VERSION 5.8 ;
BUSBITCHARS "[]" ;
DIVIDERCHAR "/" ;
UNITS
    DATABASE MICRONS 1000 ;
END UNITS

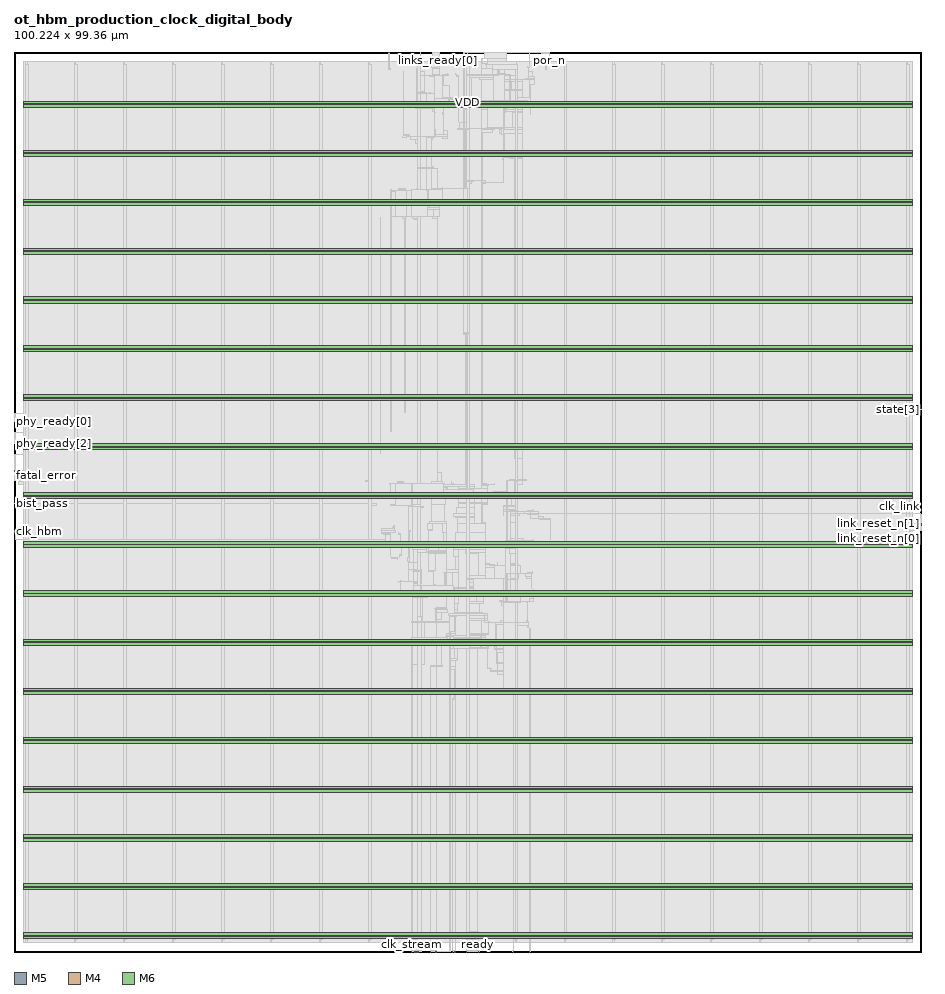
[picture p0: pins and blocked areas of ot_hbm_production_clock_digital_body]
MACRO ot_hbm_production_clock_digital_body
  FOREIGN ot_hbm_production_clock_digital_body 0 0 ;
  CLASS BLOCK ;
  SIZE 100.224 BY 99.36 ;
  PIN aon_clk
    DIRECTION INPUT ;
    USE SIGNAL ;
    PORT
      LAYER M5 ;
        RECT  58.368 99.276 58.392 99.36 ;
    END
  END aon_clk
  PIN bist_done
    DIRECTION INPUT ;
    USE SIGNAL ;
    PORT
      LAYER M5 ;
        RECT  54.336 99.276 54.36 99.36 ;
    END
  END bist_done
  PIN bist_pass
    DIRECTION INPUT ;
    USE SIGNAL ;
    PORT
      LAYER M4 ;
        RECT  0 49.536 0.084 49.56 ;
    END
  END bist_pass
  PIN clk_hbm
    DIRECTION INPUT ;
    USE SIGNAL ;
    PORT
      LAYER M4 ;
        RECT  0 46.464 0.084 46.488 ;
    END
  END clk_hbm
  PIN clk_link
    DIRECTION INPUT ;
    USE SIGNAL ;
    PORT
      LAYER M4 ;
        RECT  100.14 48.288 100.224 48.312 ;
    END
  END clk_link
  PIN clk_serial
    DIRECTION INPUT ;
    USE SIGNAL ;
    PORT
      LAYER M5 ;
        RECT  46.56 0 46.584 0.084 ;
    END
  END clk_serial
  PIN clk_stream
    DIRECTION INPUT ;
    USE SIGNAL ;
    PORT
      LAYER M5 ;
        RECT  43.872 0 43.896 0.084 ;
    END
  END clk_stream
  PIN cmd_reset_serial_n
    DIRECTION OUTPUT ;
    USE SIGNAL ;
    PORT
      LAYER M5 ;
        RECT  56.928 0 56.952 0.084 ;
    END
  END cmd_reset_serial_n
  PIN cmd_reset_stream_n
    DIRECTION OUTPUT ;
    USE SIGNAL ;
    PORT
      LAYER M5 ;
        RECT  55.104 0 55.128 0.084 ;
    END
  END cmd_reset_stream_n
  PIN coll_reset_serial_n
    DIRECTION OUTPUT ;
    USE SIGNAL ;
    PORT
      LAYER M5 ;
        RECT  48.384 0 48.408 0.084 ;
    END
  END coll_reset_serial_n
  PIN coll_reset_stream_n
    DIRECTION OUTPUT ;
    USE SIGNAL ;
    PORT
      LAYER M5 ;
        RECT  45.984 0 46.008 0.084 ;
    END
  END coll_reset_stream_n
  PIN fatal_error
    DIRECTION INPUT ;
    USE SIGNAL ;
    PORT
      LAYER M4 ;
        RECT  0 52.608 0.084 52.632 ;
    END
  END fatal_error
  PIN link_reset_n[0]
    DIRECTION OUTPUT ;
    USE SIGNAL ;
    PORT
      LAYER M4 ;
        RECT  100.14 46.56 100.224 46.584 ;
    END
  END link_reset_n[0]
  PIN link_reset_n[1]
    DIRECTION OUTPUT ;
    USE SIGNAL ;
    PORT
      LAYER M4 ;
        RECT  100.14 47.328 100.224 47.352 ;
    END
  END link_reset_n[1]
  PIN link_reset_n[2]
    DIRECTION OUTPUT ;
    USE SIGNAL ;
    PORT
      LAYER M4 ;
        RECT  100.14 46.848 100.224 46.872 ;
    END
  END link_reset_n[2]
  PIN link_reset_n[3]
    DIRECTION OUTPUT ;
    USE SIGNAL ;
    PORT
      LAYER M4 ;
        RECT  100.14 46.944 100.224 46.968 ;
    END
  END link_reset_n[3]
  PIN link_reset_n[4]
    DIRECTION OUTPUT ;
    USE SIGNAL ;
    PORT
      LAYER M4 ;
        RECT  100.14 47.232 100.224 47.256 ;
    END
  END link_reset_n[4]
  PIN link_reset_n[5]
    DIRECTION OUTPUT ;
    USE SIGNAL ;
    PORT
      LAYER M4 ;
        RECT  100.14 46.752 100.224 46.776 ;
    END
  END link_reset_n[5]
  PIN link_reset_n[6]
    DIRECTION OUTPUT ;
    USE SIGNAL ;
    PORT
      LAYER M4 ;
        RECT  100.14 47.04 100.224 47.064 ;
    END
  END link_reset_n[6]
  PIN link_reset_n[7]
    DIRECTION OUTPUT ;
    USE SIGNAL ;
    PORT
      LAYER M4 ;
        RECT  100.14 47.136 100.224 47.16 ;
    END
  END link_reset_n[7]
  PIN link_reset_n[8]
    DIRECTION OUTPUT ;
    USE SIGNAL ;
    PORT
      LAYER M4 ;
        RECT  100.14 46.656 100.224 46.68 ;
    END
  END link_reset_n[8]
  PIN links_ready[0]
    DIRECTION INPUT ;
    USE SIGNAL ;
    PORT
      LAYER M5 ;
        RECT  46.752 99.276 46.776 99.36 ;
    END
  END links_ready[0]
  PIN links_ready[1]
    DIRECTION INPUT ;
    USE SIGNAL ;
    PORT
      LAYER M5 ;
        RECT  46.944 99.276 46.968 99.36 ;
    END
  END links_ready[1]
  PIN links_ready[2]
    DIRECTION INPUT ;
    USE SIGNAL ;
    PORT
      LAYER M5 ;
        RECT  53.472 99.276 53.496 99.36 ;
    END
  END links_ready[2]
  PIN links_ready[3]
    DIRECTION INPUT ;
    USE SIGNAL ;
    PORT
      LAYER M5 ;
        RECT  52.224 99.276 52.248 99.36 ;
    END
  END links_ready[3]
  PIN links_ready[4]
    DIRECTION INPUT ;
    USE SIGNAL ;
    PORT
      LAYER M5 ;
        RECT  56.928 99.276 56.952 99.36 ;
    END
  END links_ready[4]
  PIN links_ready[5]
    DIRECTION INPUT ;
    USE SIGNAL ;
    PORT
      LAYER M5 ;
        RECT  52.8 99.276 52.824 99.36 ;
    END
  END links_ready[5]
  PIN links_ready[6]
    DIRECTION INPUT ;
    USE SIGNAL ;
    PORT
      LAYER M5 ;
        RECT  50.016 99.276 50.04 99.36 ;
    END
  END links_ready[6]
  PIN links_ready[7]
    DIRECTION INPUT ;
    USE SIGNAL ;
    PORT
      LAYER M5 ;
        RECT  44.832 99.276 44.856 99.36 ;
    END
  END links_ready[7]
  PIN links_ready[8]
    DIRECTION INPUT ;
    USE SIGNAL ;
    PORT
      LAYER M5 ;
        RECT  46.176 99.276 46.2 99.36 ;
    END
  END links_ready[8]
  PIN phy_ready[0]
    DIRECTION INPUT ;
    USE SIGNAL ;
    PORT
      LAYER M4 ;
        RECT  0 58.56 0.084 58.584 ;
    END
  END phy_ready[0]
  PIN phy_ready[1]
    DIRECTION INPUT ;
    USE SIGNAL ;
    PORT
      LAYER M5 ;
        RECT  41.376 99.276 41.4 99.36 ;
    END
  END phy_ready[1]
  PIN phy_ready[2]
    DIRECTION INPUT ;
    USE SIGNAL ;
    PORT
      LAYER M4 ;
        RECT  0 56.16 0.084 56.184 ;
    END
  END phy_ready[2]
  PIN phy_ready[3]
    DIRECTION INPUT ;
    USE SIGNAL ;
    PORT
      LAYER M4 ;
        RECT  0 54.048 0.084 54.072 ;
    END
  END phy_ready[3]
  PIN phy_reset_n[0]
    DIRECTION OUTPUT ;
    USE SIGNAL ;
    PORT
      LAYER M5 ;
        RECT  44.544 0 44.568 0.084 ;
    END
  END phy_reset_n[0]
  PIN phy_reset_n[1]
    DIRECTION OUTPUT ;
    USE SIGNAL ;
    PORT
      LAYER M5 ;
        RECT  44.256 0 44.28 0.084 ;
    END
  END phy_reset_n[1]
  PIN phy_reset_n[2]
    DIRECTION OUTPUT ;
    USE SIGNAL ;
    PORT
      LAYER M5 ;
        RECT  44.352 0 44.376 0.084 ;
    END
  END phy_reset_n[2]
  PIN phy_reset_n[3]
    DIRECTION OUTPUT ;
    USE SIGNAL ;
    PORT
      LAYER M5 ;
        RECT  44.448 0 44.472 0.084 ;
    END
  END phy_reset_n[3]
  PIN pll_lock
    DIRECTION INPUT ;
    USE SIGNAL ;
    PORT
      LAYER M5 ;
        RECT  44.64 0 44.664 0.084 ;
    END
  END pll_lock
  PIN pll_reset_n
    DIRECTION OUTPUT ;
    USE SIGNAL ;
    PORT
      LAYER M5 ;
        RECT  49.92 0 49.944 0.084 ;
    END
  END pll_reset_n
  PIN por_n
    DIRECTION INPUT ;
    USE SIGNAL ;
    PORT
      LAYER M5 ;
        RECT  59.136 99.276 59.16 99.36 ;
    END
  END por_n
  PIN power_good
    DIRECTION INPUT ;
    USE SIGNAL ;
    PORT
      LAYER M4 ;
        RECT  0 52.032 0.084 52.056 ;
    END
  END power_good
  PIN ready
    DIRECTION OUTPUT ;
    USE SIGNAL ;
    PORT
      LAYER M5 ;
        RECT  51.264 0 51.288 0.084 ;
    END
  END ready
  PIN requalify
    DIRECTION INPUT ;
    USE SIGNAL ;
    PORT
      LAYER M4 ;
        RECT  0 53.088 0.084 53.112 ;
    END
  END requalify
  PIN state[0]
    DIRECTION OUTPUT ;
    USE SIGNAL ;
    PORT
      LAYER M5 ;
        RECT  46.656 0 46.68 0.084 ;
    END
  END state[0]
  PIN state[1]
    DIRECTION OUTPUT ;
    USE SIGNAL ;
    PORT
      LAYER M5 ;
        RECT  48.672 0 48.696 0.084 ;
    END
  END state[1]
  PIN state[2]
    DIRECTION OUTPUT ;
    USE SIGNAL ;
    PORT
      LAYER M5 ;
        RECT  51.936 99.276 51.96 99.36 ;
    END
  END state[2]
  PIN state[3]
    DIRECTION OUTPUT ;
    USE SIGNAL ;
    PORT
      LAYER M4 ;
        RECT  100.14 59.904 100.224 59.928 ;
    END
  END state[3]
  PIN VDD
    DIRECTION INOUT ;
    USE POWER ;
    PORT
      LAYER M6 ;
        RECT  1.08 93.633 99.144 93.921 ;
        RECT  1.08 88.233 99.144 88.521 ;
        RECT  1.08 82.833 99.144 83.121 ;
        RECT  1.08 77.433 99.144 77.721 ;
        RECT  1.08 72.033 99.144 72.321 ;
        RECT  1.08 66.633 99.144 66.921 ;
        RECT  1.08 61.233 99.144 61.521 ;
        RECT  1.08 55.833 99.144 56.121 ;
        RECT  1.08 50.433 99.144 50.721 ;
        RECT  1.08 45.033 99.144 45.321 ;
        RECT  1.08 39.633 99.144 39.921 ;
        RECT  1.08 34.233 99.144 34.521 ;
        RECT  1.08 28.833 99.144 29.121 ;
        RECT  1.08 23.433 99.144 23.721 ;
        RECT  1.08 18.033 99.144 18.321 ;
        RECT  1.08 12.633 99.144 12.921 ;
        RECT  1.08 7.233 99.144 7.521 ;
        RECT  1.08 1.833 99.144 2.121 ;
    END
  END VDD
  PIN VSS
    DIRECTION INOUT ;
    USE GROUND ;
    PORT
      LAYER M6 ;
        RECT  1.08 93.249 99.144 93.537 ;
        RECT  1.08 87.849 99.144 88.137 ;
        RECT  1.08 82.449 99.144 82.737 ;
        RECT  1.08 77.049 99.144 77.337 ;
        RECT  1.08 71.649 99.144 71.937 ;
        RECT  1.08 66.249 99.144 66.537 ;
        RECT  1.08 60.849 99.144 61.137 ;
        RECT  1.08 55.449 99.144 55.737 ;
        RECT  1.08 50.049 99.144 50.337 ;
        RECT  1.08 44.649 99.144 44.937 ;
        RECT  1.08 39.249 99.144 39.537 ;
        RECT  1.08 33.849 99.144 34.137 ;
        RECT  1.08 28.449 99.144 28.737 ;
        RECT  1.08 23.049 99.144 23.337 ;
        RECT  1.08 17.649 99.144 17.937 ;
        RECT  1.08 12.249 99.144 12.537 ;
        RECT  1.08 6.849 99.144 7.137 ;
        RECT  1.08 1.449 99.144 1.737 ;
    END
  END VSS
  OBS
    LAYER RVTN ;
     RECT  1.08 1.08 99.144 1.215 ;
     RECT  1.08 1.485 99.144 1.755 ;
     RECT  1.08 2.025 99.144 2.295 ;
     RECT  1.08 2.565 99.144 2.835 ;
     RECT  1.08 3.105 99.144 3.375 ;
     RECT  1.08 3.645 99.144 3.915 ;
     RECT  1.08 4.185 99.144 4.455 ;
     RECT  1.08 4.725 99.144 4.995 ;
     RECT  1.08 5.265 99.144 5.535 ;
     RECT  1.08 5.805 99.144 6.075 ;
     RECT  1.08 6.345 99.144 6.615 ;
     RECT  1.08 6.885 99.144 7.155 ;
     RECT  1.08 7.425 99.144 7.695 ;
     RECT  1.08 7.965 99.144 8.235 ;
     RECT  1.08 8.505 99.144 8.775 ;
     RECT  1.08 9.045 99.144 9.315 ;
     RECT  1.08 9.585 99.144 9.855 ;
     RECT  1.08 10.125 99.144 10.395 ;
     RECT  1.08 10.665 99.144 10.935 ;
     RECT  1.08 11.205 99.144 11.475 ;
     RECT  1.08 11.745 99.144 12.015 ;
     RECT  1.08 12.285 99.144 12.555 ;
     RECT  1.08 12.825 99.144 13.095 ;
     RECT  1.08 13.365 99.144 13.635 ;
     RECT  1.08 13.905 99.144 14.175 ;
     RECT  1.08 14.445 99.144 14.715 ;
     RECT  1.08 14.985 99.144 15.255 ;
     RECT  1.08 15.525 99.144 15.795 ;
     RECT  1.08 16.065 99.144 16.335 ;
     RECT  1.08 16.605 99.144 16.875 ;
     RECT  1.08 17.145 99.144 17.415 ;
     RECT  1.08 17.685 99.144 17.955 ;
     RECT  1.08 18.225 99.144 18.495 ;
     RECT  1.08 18.765 99.144 19.035 ;
     RECT  1.08 19.305 99.144 19.575 ;
     RECT  1.08 19.845 99.144 20.115 ;
     RECT  1.08 20.385 99.144 20.655 ;
     RECT  1.08 20.925 99.144 21.195 ;
     RECT  1.08 21.465 99.144 21.735 ;
     RECT  1.08 22.005 99.144 22.275 ;
     RECT  1.08 22.545 99.144 22.815 ;
     RECT  1.08 23.085 99.144 23.355 ;
     RECT  1.08 23.625 99.144 23.895 ;
     RECT  1.08 24.165 99.144 24.435 ;
     RECT  1.08 24.705 99.144 24.975 ;
     RECT  1.08 25.245 99.144 25.515 ;
     RECT  1.08 25.785 99.144 26.055 ;
     RECT  1.08 26.325 99.144 26.595 ;
     RECT  1.08 26.865 99.144 27.135 ;
     RECT  1.08 27.405 99.144 27.675 ;
     RECT  1.08 27.945 99.144 28.215 ;
     RECT  1.08 28.485 99.144 28.755 ;
     RECT  1.08 29.025 99.144 29.295 ;
     RECT  1.08 29.565 99.144 29.835 ;
     RECT  1.08 30.105 99.144 30.375 ;
     RECT  1.08 30.645 99.144 30.915 ;
     RECT  1.08 31.185 99.144 31.455 ;
     RECT  1.08 31.725 99.144 31.995 ;
     RECT  1.08 32.265 99.144 32.535 ;
     RECT  1.08 32.805 99.144 33.075 ;
     RECT  1.08 33.345 99.144 33.615 ;
     RECT  1.08 33.885 99.144 34.155 ;
     RECT  1.08 34.425 99.144 34.695 ;
     RECT  1.08 34.965 99.144 35.235 ;
     RECT  1.08 35.505 99.144 35.775 ;
     RECT  1.08 36.045 99.144 36.315 ;
     RECT  1.08 36.585 99.144 36.855 ;
     RECT  1.08 37.125 99.144 37.395 ;
     RECT  1.08 37.665 99.144 37.935 ;
     RECT  1.08 38.205 99.144 38.475 ;
     RECT  1.08 38.745 99.144 39.015 ;
     RECT  1.08 39.285 99.144 39.555 ;
     RECT  1.08 39.825 99.144 40.095 ;
     RECT  1.08 40.365 99.144 40.635 ;
     RECT  1.08 40.905 99.144 41.175 ;
     RECT  1.08 41.445 99.144 41.715 ;
     RECT  1.08 41.985 99.144 42.255 ;
     RECT  1.08 42.525 99.144 42.795 ;
     RECT  1.08 43.065 99.144 43.335 ;
     RECT  1.08 43.605 99.144 43.875 ;
     RECT  1.08 44.145 99.144 44.415 ;
     RECT  1.08 44.685 99.144 44.955 ;
     RECT  1.08 45.225 99.144 45.495 ;
     RECT  1.08 45.765 99.144 46.035 ;
     RECT  1.08 46.305 99.144 46.575 ;
     RECT  1.08 46.845 99.144 47.115 ;
     RECT  1.08 47.385 99.144 47.655 ;
     RECT  1.08 47.925 99.144 48.195 ;
     RECT  1.08 48.465 99.144 48.735 ;
     RECT  1.08 49.005 99.144 49.275 ;
     RECT  1.08 49.545 99.144 49.815 ;
     RECT  1.08 50.085 99.144 50.355 ;
     RECT  1.08 50.625 99.144 50.895 ;
     RECT  1.08 51.165 99.144 51.435 ;
     RECT  1.08 51.705 99.144 51.975 ;
     RECT  1.08 52.245 99.144 52.515 ;
     RECT  1.08 52.785 99.144 53.055 ;
     RECT  1.08 53.325 99.144 53.595 ;
     RECT  1.08 53.865 99.144 54.135 ;
     RECT  1.08 54.405 99.144 54.675 ;
     RECT  1.08 54.945 99.144 55.215 ;
     RECT  1.08 55.485 99.144 55.755 ;
     RECT  1.08 56.025 99.144 56.295 ;
     RECT  1.08 56.565 99.144 56.835 ;
     RECT  1.08 57.105 99.144 57.375 ;
     RECT  1.08 57.645 99.144 57.915 ;
     RECT  1.08 58.185 99.144 58.455 ;
     RECT  1.08 58.725 99.144 58.995 ;
     RECT  1.08 59.265 99.144 59.535 ;
     RECT  1.08 59.805 99.144 60.075 ;
     RECT  1.08 60.345 99.144 60.615 ;
     RECT  1.08 60.885 99.144 61.155 ;
     RECT  1.08 61.425 99.144 61.695 ;
     RECT  1.08 61.965 99.144 62.235 ;
     RECT  1.08 62.505 99.144 62.775 ;
     RECT  1.08 63.045 99.144 63.315 ;
     RECT  1.08 63.585 99.144 63.855 ;
     RECT  1.08 64.125 99.144 64.395 ;
     RECT  1.08 64.665 99.144 64.935 ;
     RECT  1.08 65.205 99.144 65.475 ;
     RECT  1.08 65.745 99.144 66.015 ;
     RECT  1.08 66.285 99.144 66.555 ;
     RECT  1.08 66.825 99.144 67.095 ;
     RECT  1.08 67.365 99.144 67.635 ;
     RECT  1.08 67.905 99.144 68.175 ;
     RECT  1.08 68.445 99.144 68.715 ;
     RECT  1.08 68.985 99.144 69.255 ;
     RECT  1.08 69.525 99.144 69.795 ;
     RECT  1.08 70.065 99.144 70.335 ;
     RECT  1.08 70.605 99.144 70.875 ;
     RECT  1.08 71.145 99.144 71.415 ;
     RECT  1.08 71.685 99.144 71.955 ;
     RECT  1.08 72.225 99.144 72.495 ;
     RECT  1.08 72.765 99.144 73.035 ;
     RECT  1.08 73.305 99.144 73.575 ;
     RECT  1.08 73.845 99.144 74.115 ;
     RECT  1.08 74.385 99.144 74.655 ;
     RECT  1.08 74.925 99.144 75.195 ;
     RECT  1.08 75.465 99.144 75.735 ;
     RECT  1.08 76.005 99.144 76.275 ;
     RECT  1.08 76.545 99.144 76.815 ;
     RECT  1.08 77.085 99.144 77.355 ;
     RECT  1.08 77.625 99.144 77.895 ;
     RECT  1.08 78.165 99.144 78.435 ;
     RECT  1.08 78.705 99.144 78.975 ;
     RECT  1.08 79.245 99.144 79.515 ;
     RECT  1.08 79.785 99.144 80.055 ;
     RECT  1.08 80.325 99.144 80.595 ;
     RECT  1.08 80.865 99.144 81.135 ;
     RECT  1.08 81.405 99.144 81.675 ;
     RECT  1.08 81.945 99.144 82.215 ;
     RECT  1.08 82.485 99.144 82.755 ;
     RECT  1.08 83.025 99.144 83.295 ;
     RECT  1.08 83.565 99.144 83.835 ;
     RECT  1.08 84.105 99.144 84.375 ;
     RECT  1.08 84.645 99.144 84.915 ;
     RECT  1.08 85.185 99.144 85.455 ;
     RECT  1.08 85.725 99.144 85.995 ;
     RECT  1.08 86.265 99.144 86.535 ;
     RECT  1.08 86.805 99.144 87.075 ;
     RECT  1.08 87.345 99.144 87.615 ;
     RECT  1.08 87.885 99.144 88.155 ;
     RECT  1.08 88.425 99.144 88.695 ;
     RECT  1.08 88.965 99.144 89.235 ;
     RECT  1.08 89.505 99.144 89.775 ;
     RECT  1.08 90.045 99.144 90.315 ;
     RECT  1.08 90.585 99.144 90.855 ;
     RECT  1.08 91.125 99.144 91.395 ;
     RECT  1.08 91.665 99.144 91.935 ;
     RECT  1.08 92.205 99.144 92.475 ;
     RECT  1.08 92.745 99.144 93.015 ;
     RECT  1.08 93.285 99.144 93.555 ;
     RECT  1.08 93.825 99.144 94.095 ;
     RECT  1.08 94.365 99.144 94.635 ;
     RECT  1.08 94.905 99.144 95.175 ;
     RECT  1.08 95.445 99.144 95.715 ;
     RECT  1.08 95.985 99.144 96.255 ;
     RECT  1.08 96.525 99.144 96.795 ;
     RECT  1.08 97.065 99.144 97.335 ;
     RECT  1.08 97.605 99.144 97.875 ;
     RECT  1.08 98.145 99.144 98.28 ;
    LAYER RVTP ;
     RECT  1.08 1.215 99.144 1.485 ;
     RECT  1.08 1.755 99.144 2.025 ;
     RECT  1.08 2.295 99.144 2.565 ;
     RECT  1.08 2.835 99.144 3.105 ;
     RECT  1.08 3.375 99.144 3.645 ;
     RECT  1.08 3.915 99.144 4.185 ;
     RECT  1.08 4.455 99.144 4.725 ;
     RECT  1.08 4.995 99.144 5.265 ;
     RECT  1.08 5.535 99.144 5.805 ;
     RECT  1.08 6.075 99.144 6.345 ;
     RECT  1.08 6.615 99.144 6.885 ;
     RECT  1.08 7.155 99.144 7.425 ;
     RECT  1.08 7.695 99.144 7.965 ;
     RECT  1.08 8.235 99.144 8.505 ;
     RECT  1.08 8.775 99.144 9.045 ;
     RECT  1.08 9.315 99.144 9.585 ;
     RECT  1.08 9.855 99.144 10.125 ;
     RECT  1.08 10.395 99.144 10.665 ;
     RECT  1.08 10.935 99.144 11.205 ;
     RECT  1.08 11.475 99.144 11.745 ;
     RECT  1.08 12.015 99.144 12.285 ;
     RECT  1.08 12.555 99.144 12.825 ;
     RECT  1.08 13.095 99.144 13.365 ;
     RECT  1.08 13.635 99.144 13.905 ;
     RECT  1.08 14.175 99.144 14.445 ;
     RECT  1.08 14.715 99.144 14.985 ;
     RECT  1.08 15.255 99.144 15.525 ;
     RECT  1.08 15.795 99.144 16.065 ;
     RECT  1.08 16.335 99.144 16.605 ;
     RECT  1.08 16.875 99.144 17.145 ;
     RECT  1.08 17.415 99.144 17.685 ;
     RECT  1.08 17.955 99.144 18.225 ;
     RECT  1.08 18.495 99.144 18.765 ;
     RECT  1.08 19.035 99.144 19.305 ;
     RECT  1.08 19.575 99.144 19.845 ;
     RECT  1.08 20.115 99.144 20.385 ;
     RECT  1.08 20.655 99.144 20.925 ;
     RECT  1.08 21.195 99.144 21.465 ;
     RECT  1.08 21.735 99.144 22.005 ;
     RECT  1.08 22.275 99.144 22.545 ;
     RECT  1.08 22.815 99.144 23.085 ;
     RECT  1.08 23.355 99.144 23.625 ;
     RECT  1.08 23.895 99.144 24.165 ;
     RECT  1.08 24.435 99.144 24.705 ;
     RECT  1.08 24.975 99.144 25.245 ;
     RECT  1.08 25.515 99.144 25.785 ;
     RECT  1.08 26.055 99.144 26.325 ;
     RECT  1.08 26.595 99.144 26.865 ;
     RECT  1.08 27.135 99.144 27.405 ;
     RECT  1.08 27.675 99.144 27.945 ;
     RECT  1.08 28.215 99.144 28.485 ;
     RECT  1.08 28.755 99.144 29.025 ;
     RECT  1.08 29.295 99.144 29.565 ;
     RECT  1.08 29.835 99.144 30.105 ;
     RECT  1.08 30.375 99.144 30.645 ;
     RECT  1.08 30.915 99.144 31.185 ;
     RECT  1.08 31.455 99.144 31.725 ;
     RECT  1.08 31.995 99.144 32.265 ;
     RECT  1.08 32.535 99.144 32.805 ;
     RECT  1.08 33.075 99.144 33.345 ;
     RECT  1.08 33.615 99.144 33.885 ;
     RECT  1.08 34.155 99.144 34.425 ;
     RECT  1.08 34.695 99.144 34.965 ;
     RECT  1.08 35.235 99.144 35.505 ;
     RECT  1.08 35.775 99.144 36.045 ;
     RECT  1.08 36.315 99.144 36.585 ;
     RECT  1.08 36.855 99.144 37.125 ;
     RECT  1.08 37.395 99.144 37.665 ;
     RECT  1.08 37.935 99.144 38.205 ;
     RECT  1.08 38.475 99.144 38.745 ;
     RECT  1.08 39.015 99.144 39.285 ;
     RECT  1.08 39.555 99.144 39.825 ;
     RECT  1.08 40.095 99.144 40.365 ;
     RECT  1.08 40.635 99.144 40.905 ;
     RECT  1.08 41.175 99.144 41.445 ;
     RECT  1.08 41.715 99.144 41.985 ;
     RECT  1.08 42.255 99.144 42.525 ;
     RECT  1.08 42.795 99.144 43.065 ;
     RECT  1.08 43.335 99.144 43.605 ;
     RECT  1.08 43.875 99.144 44.145 ;
     RECT  1.08 44.415 99.144 44.685 ;
     RECT  1.08 44.955 99.144 45.225 ;
     RECT  1.08 45.495 99.144 45.765 ;
     RECT  1.08 46.035 99.144 46.305 ;
     RECT  1.08 46.575 99.144 46.845 ;
     RECT  1.08 47.115 99.144 47.385 ;
     RECT  1.08 47.655 99.144 47.925 ;
     RECT  1.08 48.195 99.144 48.465 ;
     RECT  1.08 48.735 99.144 49.005 ;
     RECT  1.08 49.275 99.144 49.545 ;
     RECT  1.08 49.815 99.144 50.085 ;
     RECT  1.08 50.355 99.144 50.625 ;
     RECT  1.08 50.895 99.144 51.165 ;
     RECT  1.08 51.435 99.144 51.705 ;
     RECT  1.08 51.975 99.144 52.245 ;
     RECT  1.08 52.515 99.144 52.785 ;
     RECT  1.08 53.055 99.144 53.325 ;
     RECT  1.08 53.595 99.144 53.865 ;
     RECT  1.08 54.135 99.144 54.405 ;
     RECT  1.08 54.675 99.144 54.945 ;
     RECT  1.08 55.215 99.144 55.485 ;
     RECT  1.08 55.755 99.144 56.025 ;
     RECT  1.08 56.295 99.144 56.565 ;
     RECT  1.08 56.835 99.144 57.105 ;
     RECT  1.08 57.375 99.144 57.645 ;
     RECT  1.08 57.915 99.144 58.185 ;
     RECT  1.08 58.455 99.144 58.725 ;
     RECT  1.08 58.995 99.144 59.265 ;
     RECT  1.08 59.535 99.144 59.805 ;
     RECT  1.08 60.075 99.144 60.345 ;
     RECT  1.08 60.615 99.144 60.885 ;
     RECT  1.08 61.155 99.144 61.425 ;
     RECT  1.08 61.695 99.144 61.965 ;
     RECT  1.08 62.235 99.144 62.505 ;
     RECT  1.08 62.775 99.144 63.045 ;
     RECT  1.08 63.315 99.144 63.585 ;
     RECT  1.08 63.855 99.144 64.125 ;
     RECT  1.08 64.395 99.144 64.665 ;
     RECT  1.08 64.935 99.144 65.205 ;
     RECT  1.08 65.475 99.144 65.745 ;
     RECT  1.08 66.015 99.144 66.285 ;
     RECT  1.08 66.555 99.144 66.825 ;
     RECT  1.08 67.095 99.144 67.365 ;
     RECT  1.08 67.635 99.144 67.905 ;
     RECT  1.08 68.175 99.144 68.445 ;
     RECT  1.08 68.715 99.144 68.985 ;
     RECT  1.08 69.255 99.144 69.525 ;
     RECT  1.08 69.795 99.144 70.065 ;
     RECT  1.08 70.335 99.144 70.605 ;
     RECT  1.08 70.875 99.144 71.145 ;
     RECT  1.08 71.415 99.144 71.685 ;
     RECT  1.08 71.955 99.144 72.225 ;
     RECT  1.08 72.495 99.144 72.765 ;
     RECT  1.08 73.035 99.144 73.305 ;
     RECT  1.08 73.575 99.144 73.845 ;
     RECT  1.08 74.115 99.144 74.385 ;
     RECT  1.08 74.655 99.144 74.925 ;
     RECT  1.08 75.195 99.144 75.465 ;
     RECT  1.08 75.735 99.144 76.005 ;
     RECT  1.08 76.275 99.144 76.545 ;
     RECT  1.08 76.815 99.144 77.085 ;
     RECT  1.08 77.355 99.144 77.625 ;
     RECT  1.08 77.895 99.144 78.165 ;
     RECT  1.08 78.435 99.144 78.705 ;
     RECT  1.08 78.975 99.144 79.245 ;
     RECT  1.08 79.515 99.144 79.785 ;
     RECT  1.08 80.055 99.144 80.325 ;
     RECT  1.08 80.595 99.144 80.865 ;
     RECT  1.08 81.135 99.144 81.405 ;
     RECT  1.08 81.675 99.144 81.945 ;
     RECT  1.08 82.215 99.144 82.485 ;
     RECT  1.08 82.755 99.144 83.025 ;
     RECT  1.08 83.295 99.144 83.565 ;
     RECT  1.08 83.835 99.144 84.105 ;
     RECT  1.08 84.375 99.144 84.645 ;
     RECT  1.08 84.915 99.144 85.185 ;
     RECT  1.08 85.455 99.144 85.725 ;
     RECT  1.08 85.995 99.144 86.265 ;
     RECT  1.08 86.535 99.144 86.805 ;
     RECT  1.08 87.075 99.144 87.345 ;
     RECT  1.08 87.615 99.144 87.885 ;
     RECT  1.08 88.155 99.144 88.425 ;
     RECT  1.08 88.695 99.144 88.965 ;
     RECT  1.08 89.235 99.144 89.505 ;
     RECT  1.08 89.775 99.144 90.045 ;
     RECT  1.08 90.315 99.144 90.585 ;
     RECT  1.08 90.855 99.144 91.125 ;
     RECT  1.08 91.395 99.144 91.665 ;
     RECT  1.08 91.935 99.144 92.205 ;
     RECT  1.08 92.475 99.144 92.745 ;
     RECT  1.08 93.015 99.144 93.285 ;
     RECT  1.08 93.555 99.144 93.825 ;
     RECT  1.08 94.095 99.144 94.365 ;
     RECT  1.08 94.635 99.144 94.905 ;
     RECT  1.08 95.175 99.144 95.445 ;
     RECT  1.08 95.715 99.144 95.985 ;
     RECT  1.08 96.255 99.144 96.525 ;
     RECT  1.08 96.795 99.144 97.065 ;
     RECT  1.08 97.335 99.144 97.605 ;
     RECT  1.08 97.875 99.144 98.145 ;
    LAYER M1 ;
     RECT  1.08 1.071 99.144 98.289 ;
    LAYER M2 ;
     RECT  0.499 51.642 0.535 51.66 ;
     RECT  0.535 51.642 1.08 51.966 ;
     RECT  0.535 52.992 1.08 53.01 ;
     RECT  0.103 54.882 1.08 54.9 ;
     RECT  0.103 57.312 1.08 57.33 ;
     RECT  0.103 59.472 1.08 59.49 ;
     RECT  1.08 1.071 99.144 98.289 ;
     RECT  99.144 47.124 99.167 47.214 ;
     RECT  99.167 47.124 99.203 47.142 ;
    LAYER M3 ;
     RECT  46.008 0.091 46.026 0.523 ;
     RECT  44.136 0.091 44.154 0.811 ;
     RECT  44.136 0.811 44.478 0.907 ;
     RECT  44.136 0.907 44.514 1.063 ;
     RECT  55.116 0.091 55.134 1.063 ;
     RECT  1.335 1.063 1.425 1.333 ;
     RECT  6.735 1.063 6.825 1.333 ;
     RECT  12.135 1.063 12.225 1.333 ;
     RECT  17.535 1.063 17.625 1.333 ;
     RECT  22.935 1.063 23.025 1.333 ;
     RECT  28.335 1.063 28.425 1.333 ;
     RECT  33.735 1.063 33.825 1.333 ;
     RECT  39.135 1.063 39.225 1.333 ;
     RECT  44.136 1.063 44.625 1.333 ;
     RECT  49.935 1.063 50.025 1.333 ;
     RECT  50.904 0.091 51.282 1.333 ;
     RECT  55.116 1.063 55.425 1.333 ;
     RECT  60.735 1.063 60.825 1.333 ;
     RECT  66.135 1.063 66.225 1.333 ;
     RECT  71.535 1.063 71.625 1.333 ;
     RECT  76.935 1.063 77.025 1.333 ;
     RECT  82.335 1.063 82.425 1.333 ;
     RECT  87.735 1.063 87.825 1.333 ;
     RECT  93.135 1.063 93.225 1.333 ;
     RECT  98.535 1.063 98.625 1.333 ;
     RECT  44.136 1.333 44.817 1.795 ;
     RECT  49.935 1.333 51.282 2.219 ;
     RECT  48.708 0.091 48.726 27.931 ;
     RECT  48.528 27.931 48.726 28.139 ;
     RECT  55.116 1.333 55.617 28.409 ;
     RECT  54.072 28.417 54.09 30.685 ;
     RECT  52.632 30.955 52.65 30.991 ;
     RECT  53.388 30.685 54.09 30.991 ;
     RECT  52.632 30.991 54.09 31.109 ;
     RECT  48.6 28.139 48.726 31.225 ;
     RECT  52.632 31.109 52.65 31.325 ;
     RECT  46.008 0.523 46.674 31.495 ;
     RECT  48.024 31.225 48.726 31.523 ;
     RECT  46.008 31.495 47.178 31.531 ;
     RECT  46.008 31.531 47.358 31.649 ;
     RECT  43.992 1.795 44.817 31.765 ;
     RECT  53.424 31.109 54.09 31.891 ;
     RECT  53.316 31.891 54.09 31.919 ;
     RECT  48.132 31.523 48.726 32.161 ;
     RECT  48.132 32.161 48.942 32.369 ;
     RECT  53.316 31.919 53.334 33.115 ;
     RECT  54.072 31.919 54.09 33.115 ;
     RECT  53.316 33.115 54.09 33.385 ;
     RECT  49.935 2.219 51.21 33.511 ;
     RECT  52.992 33.385 54.09 33.539 ;
     RECT  52.236 33.547 52.254 33.611 ;
     RECT  52.992 33.539 53.226 33.683 ;
     RECT  48.672 32.369 48.942 33.925 ;
     RECT  49.86 33.511 51.21 33.925 ;
     RECT  52.092 33.691 52.11 33.925 ;
     RECT  48.672 33.925 52.11 34.079 ;
     RECT  46.656 31.649 47.178 34.231 ;
     RECT  46.656 34.231 47.538 34.393 ;
     RECT  48.672 34.079 52.002 34.393 ;
     RECT  46.656 34.393 52.002 34.397 ;
     RECT  47.628 34.397 52.002 34.727 ;
     RECT  47.7 34.727 52.002 34.889 ;
     RECT  47.7 34.889 48.906 34.925 ;
     RECT  49.935 34.889 52.002 35.041 ;
     RECT  47.7 34.925 48.726 35.159 ;
     RECT  49.935 35.041 52.398 35.159 ;
     RECT  48.096 35.159 48.726 35.357 ;
     RECT  56.952 0.091 56.97 35.699 ;
     RECT  53.208 33.683 53.226 36.085 ;
     RECT  55.335 28.409 55.617 36.085 ;
     RECT  56.664 35.815 56.754 36.085 ;
     RECT  53.208 36.085 53.298 36.121 ;
     RECT  54.072 33.539 54.09 36.121 ;
     RECT  55.335 36.085 56.754 36.331 ;
     RECT  53.136 36.121 54.09 36.347 ;
     RECT  43.992 31.765 45.27 36.379 ;
     RECT  53.28 36.347 54.09 36.383 ;
     RECT  55.332 36.331 56.754 36.383 ;
     RECT  52.38 35.159 52.398 36.391 ;
     RECT  43.848 36.379 45.27 36.419 ;
     RECT  52.38 36.391 52.542 36.509 ;
     RECT  56.628 36.383 56.754 36.509 ;
     RECT  53.748 36.383 54.09 36.545 ;
     RECT  56.628 36.509 56.682 36.545 ;
     RECT  49.935 35.159 51.57 36.625 ;
     RECT  46.656 34.397 46.674 36.661 ;
     RECT  49.935 36.625 52.326 36.779 ;
     RECT  48.636 35.357 48.726 37.051 ;
     RECT  48.096 37.051 48.726 37.057 ;
     RECT  48.096 37.057 48.906 37.201 ;
     RECT  49.935 36.779 52.29 37.201 ;
     RECT  47.952 37.201 52.29 37.319 ;
     RECT  48.636 37.319 51.75 37.427 ;
     RECT  46.656 36.661 47.214 37.435 ;
     RECT  49.935 37.427 51.75 37.463 ;
     RECT  48.636 37.427 49.014 37.769 ;
     RECT  46.656 37.435 47.826 37.859 ;
     RECT  46.656 37.859 47.718 37.867 ;
     RECT  46.512 37.867 47.718 37.931 ;
     RECT  46.656 37.931 47.718 38.003 ;
     RECT  46.656 38.003 46.674 38.129 ;
     RECT  54.072 36.545 54.09 38.209 ;
     RECT  48.672 37.769 49.014 38.479 ;
     RECT  48.672 38.479 49.05 38.515 ;
     RECT  49.935 37.463 51.39 38.515 ;
     RECT  53.82 38.209 54.09 38.551 ;
     RECT  55.335 36.383 55.617 38.551 ;
     RECT  56.664 36.545 56.682 38.551 ;
     RECT  49.935 38.515 51.858 38.669 ;
     RECT  53.82 38.551 55.617 38.669 ;
     RECT  54.396 38.669 55.617 38.677 ;
     RECT  56.592 38.551 56.682 38.677 ;
     RECT  54.396 38.677 57.33 38.717 ;
     RECT  56.592 38.717 57.33 38.741 ;
     RECT  53.64 38.713 53.658 38.765 ;
     RECT  54.396 38.717 55.617 38.975 ;
     RECT  56.88 38.741 57.33 38.975 ;
     RECT  43.992 36.419 45.09 39.091 ;
     RECT  43.992 39.091 45.63 39.209 ;
     RECT  45.612 39.209 45.63 39.245 ;
     RECT  54.72 38.975 55.617 39.479 ;
     RECT  57.312 38.975 57.33 40.055 ;
     RECT  48.672 38.515 49.086 40.135 ;
     RECT  49.935 38.669 51.066 40.135 ;
     RECT  45.936 39.253 46.35 40.171 ;
     RECT  48.672 40.135 51.066 40.171 ;
     RECT  48.492 40.171 51.066 40.261 ;
     RECT  45.936 40.171 46.962 40.289 ;
     RECT  48.456 40.261 51.066 40.289 ;
     RECT  49.935 40.289 51.066 40.333 ;
     RECT  51.84 38.669 51.858 40.333 ;
     RECT  45.936 40.289 46.53 40.369 ;
     RECT  45.756 40.369 46.53 40.445 ;
     RECT  46.332 40.445 46.53 40.595 ;
     RECT  43.992 39.209 44.874 40.639 ;
     RECT  42.624 40.639 42.642 40.711 ;
     RECT  43.596 40.639 44.874 40.711 ;
     RECT  42.624 40.711 45.018 40.829 ;
     RECT  49.935 40.333 51.858 40.837 ;
     RECT  43.308 40.829 45.018 40.865 ;
     RECT  43.416 40.865 45.018 40.901 ;
     RECT  42.48 40.837 42.498 40.925 ;
     RECT  54.828 39.479 55.617 41.131 ;
     RECT  54.396 41.131 55.617 41.171 ;
     RECT  54.792 41.171 55.617 41.251 ;
     RECT  57.096 40.171 57.114 41.251 ;
     RECT  56.556 41.251 57.114 41.413 ;
     RECT  49.935 40.837 52.038 41.549 ;
     RECT  54.792 41.251 55.71 41.755 ;
     RECT  56.52 41.413 57.114 41.755 ;
     RECT  47.7 38.003 47.718 41.791 ;
     RECT  54.792 41.755 57.114 41.791 ;
     RECT  54.792 41.791 57.258 41.792 ;
     RECT  47.664 41.791 47.718 41.851 ;
     RECT  47.52 41.851 47.718 41.909 ;
     RECT  56.7 41.792 57.258 41.909 ;
     RECT  47.7 41.909 47.718 41.917 ;
     RECT  48.456 40.289 49.086 41.917 ;
     RECT  57.24 41.909 57.258 41.981 ;
     RECT  46.332 40.595 46.35 42.061 ;
     RECT  45.792 42.061 46.35 42.151 ;
     RECT  43.596 40.901 45.018 42.179 ;
     RECT  43.596 42.179 44.874 42.215 ;
     RECT  47.7 41.917 49.086 42.215 ;
     RECT  52.02 41.549 52.038 42.421 ;
     RECT  53.064 41.341 53.082 42.421 ;
     RECT  54.792 41.792 55.89 42.719 ;
     RECT  54.792 42.719 55.71 42.791 ;
     RECT  52.02 42.421 53.082 42.827 ;
     RECT  52.02 42.827 52.542 42.863 ;
     RECT  54.792 42.791 55.638 42.863 ;
     RECT  43.596 42.215 44.817 42.989 ;
     RECT  53.352 42.835 53.37 42.989 ;
     RECT  43.596 42.989 43.614 43.141 ;
     RECT  42.3 43.303 42.318 43.411 ;
     RECT  43.488 43.141 43.614 43.529 ;
     RECT  41.724 43.411 42.318 43.565 ;
     RECT  48.708 42.215 49.086 43.645 ;
     RECT  42.516 43.573 42.534 43.771 ;
     RECT  42.516 43.771 42.786 43.871 ;
     RECT  45.792 42.151 46.53 43.951 ;
     RECT  49.935 41.549 51.282 43.951 ;
     RECT  45.792 43.951 46.854 44.041 ;
     RECT  47.7 42.215 47.718 44.041 ;
     RECT  54.792 42.863 55.617 44.041 ;
     RECT  49.86 43.951 51.282 44.077 ;
     RECT  52.02 42.863 52.038 44.077 ;
     RECT  45.792 44.041 47.718 44.149 ;
     RECT  45.54 44.149 47.718 44.189 ;
     RECT  45.792 44.189 47.718 44.375 ;
     RECT  48.528 43.645 49.086 44.383 ;
     RECT  49.86 44.077 52.038 44.383 ;
     RECT  54.684 44.041 55.617 44.587 ;
     RECT  54.252 44.587 55.617 44.645 ;
     RECT  41.58 43.609 41.598 44.725 ;
     RECT  46.836 44.375 47.718 44.879 ;
     RECT  48.528 44.383 52.038 44.879 ;
     RECT  54.396 44.645 55.617 44.879 ;
     RECT  54.72 44.879 55.617 44.959 ;
     RECT  41.58 44.725 41.922 44.971 ;
     RECT  54.72 44.959 55.926 44.987 ;
     RECT  41.328 44.971 41.922 45.005 ;
     RECT  54.792 44.987 55.926 45.031 ;
     RECT  42.768 43.871 42.786 45.149 ;
     RECT  54.792 45.031 56.61 45.157 ;
     RECT  41.328 45.005 41.598 45.193 ;
     RECT  54.792 45.157 56.898 45.301 ;
     RECT  54.792 45.301 57.33 45.455 ;
     RECT  57.312 45.455 57.33 45.527 ;
     RECT  54.792 45.455 56.214 45.599 ;
     RECT  41.004 45.193 41.598 46.111 ;
     RECT  42.66 45.265 42.678 46.111 ;
     RECT  98.535 1.333 98.817 46.111 ;
     RECT  45.792 44.375 45.81 46.201 ;
     RECT  42.408 46.111 42.678 46.229 ;
     RECT  40.752 46.111 41.598 46.237 ;
     RECT  42.408 46.229 42.426 46.265 ;
     RECT  40.608 46.237 41.598 46.273 ;
     RECT  48.78 44.879 52.038 46.301 ;
     RECT  43.596 43.529 43.614 46.345 ;
     RECT  47.376 44.879 47.718 46.345 ;
     RECT  98.535 46.111 98.946 46.345 ;
     RECT  43.524 46.345 43.614 46.381 ;
     RECT  40.608 46.273 42.066 46.499 ;
     RECT  43.524 46.381 43.758 46.499 ;
     RECT  45.756 46.201 45.81 46.579 ;
     RECT  45.756 46.579 46.206 46.615 ;
     RECT  40.608 46.499 41.958 46.769 ;
     RECT  41.436 46.769 41.958 46.805 ;
     RECT  41.796 46.805 41.958 46.841 ;
     RECT  98.496 46.345 98.946 46.921 ;
     RECT  98.496 46.921 99.018 46.939 ;
     RECT  41.868 46.841 41.958 47.039 ;
     RECT  98.496 46.939 99.162 47.047 ;
     RECT  41.868 47.039 41.886 47.075 ;
     RECT  98.244 47.047 99.162 47.119 ;
     RECT  98.244 47.119 99.198 47.261 ;
     RECT  59.256 45.571 59.274 47.309 ;
     RECT  98.244 47.261 99.018 47.309 ;
     RECT  45.648 46.615 46.206 47.345 ;
     RECT  48.96 46.301 52.038 47.345 ;
     RECT  45.864 47.345 46.206 47.353 ;
     RECT  47.268 46.345 47.718 47.353 ;
     RECT  98.535 47.309 99.018 47.357 ;
     RECT  51.588 47.345 52.038 47.381 ;
     RECT  54.792 45.599 55.617 47.417 ;
     RECT  45.864 47.353 47.718 47.579 ;
     RECT  59.184 47.461 59.202 47.731 ;
     RECT  58.068 47.731 59.202 47.834 ;
     RECT  57.924 47.834 59.202 47.849 ;
     RECT  57.924 47.849 58.77 47.885 ;
     RECT  48.96 47.345 50.814 48.001 ;
     RECT  48.744 48.001 50.814 48.091 ;
     RECT  57.924 47.885 58.482 48.119 ;
     RECT  54.828 47.417 55.617 48.235 ;
     RECT  56.988 47.851 57.006 48.271 ;
     RECT  57.924 48.119 57.942 48.271 ;
     RECT  54.828 48.235 55.818 48.379 ;
     RECT  48.528 48.091 50.814 48.389 ;
     RECT  54.828 48.379 55.926 48.425 ;
     RECT  54.072 48.235 54.09 48.619 ;
     RECT  54.828 48.425 55.617 48.619 ;
     RECT  56.736 48.271 57.942 48.659 ;
     RECT  56.736 48.659 57.33 48.695 ;
     RECT  56.988 48.695 57.33 48.701 ;
     RECT  54.072 48.619 55.617 48.811 ;
     RECT  57.312 48.701 57.33 48.839 ;
     RECT  51.588 47.381 51.678 49.009 ;
     RECT  44.535 42.989 44.817 49.081 ;
     RECT  48.816 48.389 50.814 49.109 ;
     RECT  43.524 46.499 43.542 49.195 ;
     RECT  44.496 49.081 45.234 49.195 ;
     RECT  43.524 49.195 45.234 49.199 ;
     RECT  54.036 48.811 55.617 49.199 ;
     RECT  43.524 49.199 44.91 49.271 ;
     RECT  39.135 1.333 39.417 49.315 ;
     RECT  42.084 49.279 42.102 49.315 ;
     RECT  54.072 49.199 55.617 49.343 ;
     RECT  41.616 49.315 42.426 49.351 ;
     RECT  43.524 49.271 43.542 49.351 ;
     RECT  46.044 47.579 47.574 49.351 ;
     RECT  41.616 49.351 43.542 49.373 ;
     RECT  51.588 49.009 51.75 49.441 ;
     RECT  42.084 49.373 43.542 49.469 ;
     RECT  42.876 49.469 43.542 49.505 ;
     RECT  49.104 49.109 50.814 49.513 ;
     RECT  51.588 49.441 52.326 49.513 ;
     RECT  39.135 49.315 40.05 49.565 ;
     RECT  43.524 49.505 43.542 49.577 ;
     RECT  44.496 49.271 44.91 49.577 ;
     RECT  49.104 49.513 52.326 49.613 ;
     RECT  49.104 49.613 50.814 50.125 ;
     RECT  49.032 50.125 50.814 50.683 ;
     RECT  51.588 49.613 52.326 50.683 ;
     RECT  49.032 50.683 52.686 50.729 ;
     RECT  46.044 49.351 47.682 51.061 ;
     RECT  49.032 50.729 52.326 51.125 ;
     RECT  46.044 51.061 47.79 51.241 ;
     RECT  46.044 51.241 47.862 51.439 ;
     RECT  49.032 51.125 50.814 51.439 ;
     RECT  44.535 49.577 44.91 51.467 ;
     RECT  51.588 51.125 52.326 51.511 ;
     RECT  51.588 51.511 52.362 51.539 ;
     RECT  51.66 51.539 52.362 51.601 ;
     RECT  46.044 51.439 50.814 51.629 ;
     RECT  51.66 51.601 53.01 51.629 ;
     RECT  42.084 49.469 42.102 51.637 ;
     RECT  44.535 51.467 44.817 51.637 ;
     RECT  54.936 49.343 55.617 51.637 ;
     RECT  41.508 51.637 42.39 51.677 ;
     RECT  43.74 51.601 43.758 51.677 ;
     RECT  46.044 51.629 47.538 51.677 ;
     RECT  42.084 51.677 42.39 51.701 ;
     RECT  46.044 51.677 47.358 51.701 ;
     RECT  48.312 51.629 48.474 51.701 ;
     RECT  52.992 51.629 53.01 51.701 ;
     RECT  51.66 51.629 52.218 51.773 ;
     RECT  42.372 51.701 42.39 51.781 ;
     RECT  42.372 51.781 43.038 51.899 ;
     RECT  46.044 51.701 47.286 51.899 ;
     RECT  42.372 51.899 42.93 51.935 ;
     RECT  44.496 51.637 44.817 51.935 ;
     RECT  48.312 51.701 48.33 51.935 ;
     RECT  0.504 51.637 0.522 51.943 ;
     RECT  39.135 49.565 39.417 51.943 ;
     RECT  38.772 51.943 39.417 52.043 ;
     RECT  54.684 51.637 56.142 52.051 ;
     RECT  0.504 51.943 0.558 52.061 ;
     RECT  54.684 52.051 56.61 52.169 ;
     RECT  46.728 51.899 47.214 52.979 ;
     RECT  0.54 52.061 0.558 53.117 ;
     RECT  55.335 52.169 56.142 54.481 ;
     RECT  0.108 54.043 0.126 54.905 ;
     RECT  0.108 56.155 0.126 57.335 ;
     RECT  0.108 58.555 0.126 59.495 ;
     RECT  98.535 47.357 98.817 59.809 ;
     RECT  98.535 59.809 99.018 59.933 ;
     RECT  49.896 51.629 50.217 68.215 ;
     RECT  49.644 68.215 50.217 68.381 ;
     RECT  44.535 51.935 44.817 80.905 ;
     RECT  43.164 59.611 43.182 80.941 ;
     RECT  44.208 80.905 44.817 80.941 ;
     RECT  46.728 52.979 46.746 80.941 ;
     RECT  40.428 55.021 40.446 81.059 ;
     RECT  41.616 57.451 41.634 81.163 ;
     RECT  42.84 80.941 43.182 81.166 ;
     RECT  43.956 80.941 44.817 81.167 ;
     RECT  44.208 81.167 44.817 81.203 ;
     RECT  42.804 81.166 43.182 81.205 ;
     RECT  46.224 80.941 46.746 81.205 ;
     RECT  44.535 81.203 44.817 81.211 ;
     RECT  45.684 81.205 46.746 81.211 ;
     RECT  41.616 81.163 41.922 81.239 ;
     RECT  42.804 81.205 43.434 81.245 ;
     RECT  44.535 81.211 46.962 81.245 ;
     RECT  42.804 81.245 43.182 81.329 ;
     RECT  43.164 81.329 43.182 81.365 ;
     RECT  44.535 81.245 45.306 81.905 ;
     RECT  46.26 81.245 46.962 82.021 ;
     RECT  45.612 82.021 46.962 82.139 ;
     RECT  45.864 82.139 46.962 83.335 ;
     RECT  45.72 83.335 46.962 83.405 ;
     RECT  41.616 81.239 41.634 83.992 ;
     RECT  41.616 83.992 41.706 84.029 ;
     RECT  42.624 83.911 42.642 84.037 ;
     RECT  44.535 81.905 44.817 84.037 ;
     RECT  43.668 84.037 43.686 84.077 ;
     RECT  42.408 84.037 42.642 84.181 ;
     RECT  46.044 83.405 46.962 84.187 ;
     RECT  41.616 84.029 41.634 84.209 ;
     RECT  42.408 84.181 43.182 84.299 ;
     RECT  46.044 84.187 47.61 84.299 ;
     RECT  46.044 84.299 47.286 84.317 ;
     RECT  42.408 84.299 42.966 84.335 ;
     RECT  44.46 84.037 44.817 84.335 ;
     RECT  49.896 68.381 50.217 84.859 ;
     RECT  51.66 51.773 51.678 84.883 ;
     RECT  51.66 84.883 52.038 84.941 ;
     RECT  49.896 84.859 50.454 85.081 ;
     RECT  49.896 85.081 50.49 85.133 ;
     RECT  44.535 84.335 44.817 86.431 ;
     RECT  46.044 84.317 46.782 86.459 ;
     RECT  44.535 86.431 44.874 86.539 ;
     RECT  46.044 86.459 46.314 86.539 ;
     RECT  44.535 86.539 46.314 86.603 ;
     RECT  46.044 86.603 46.314 86.729 ;
     RECT  53.964 87.547 53.982 87.611 ;
     RECT  55.26 54.481 56.142 87.619 ;
     RECT  54.792 87.619 56.142 87.655 ;
     RECT  54.756 87.655 56.142 87.691 ;
     RECT  44.535 86.603 44.874 89.159 ;
     RECT  44.535 89.159 44.817 89.311 ;
     RECT  44.28 89.311 44.817 89.743 ;
     RECT  46.044 86.729 46.062 89.743 ;
     RECT  46.044 89.743 46.17 89.771 ;
     RECT  46.152 89.771 46.17 89.879 ;
     RECT  49.896 85.133 50.217 89.941 ;
     RECT  43.812 89.743 44.817 89.977 ;
     RECT  47.304 89.851 47.862 89.977 ;
     RECT  42.876 89.941 42.894 89.981 ;
     RECT  46.368 89.977 46.386 90.013 ;
     RECT  47.232 89.977 47.862 90.013 ;
     RECT  46.368 90.013 47.862 90.029 ;
     RECT  43.668 89.977 44.817 90.041 ;
     RECT  43.668 90.041 43.686 90.121 ;
     RECT  43.02 90.121 43.686 90.275 ;
     RECT  46.512 90.029 47.862 90.275 ;
     RECT  54.144 87.691 56.142 90.331 ;
     RECT  53.82 90.331 56.142 90.391 ;
     RECT  51.66 84.941 51.678 90.517 ;
     RECT  52.812 90.481 52.83 90.517 ;
     RECT  49.896 89.941 50.274 90.625 ;
     RECT  49.752 90.625 50.31 90.661 ;
     RECT  47.376 90.275 47.862 90.689 ;
     RECT  46.512 90.275 46.53 90.779 ;
     RECT  49.572 90.661 50.31 90.779 ;
     RECT  53.604 90.391 56.142 90.779 ;
     RECT  49.572 90.779 50.217 90.859 ;
     RECT  51.66 90.517 52.83 90.859 ;
     RECT  48.996 90.859 50.217 90.896 ;
     RECT  51.66 90.859 53.046 90.923 ;
     RECT  53.028 90.923 53.046 91.049 ;
     RECT  54.144 90.779 56.142 91.049 ;
     RECT  49.212 90.896 50.217 91.589 ;
     RECT  47.376 90.689 47.394 92.407 ;
     RECT  46.368 90.931 46.386 92.635 ;
     RECT  46.368 92.635 46.458 92.675 ;
     RECT  54.144 91.049 54.162 92.677 ;
     RECT  55.08 91.049 56.142 92.677 ;
     RECT  47.268 92.407 47.394 92.705 ;
     RECT  46.368 92.675 46.386 92.821 ;
     RECT  49.104 91.741 49.122 92.821 ;
     RECT  54.144 92.677 54.27 92.821 ;
     RECT  55.044 92.677 56.142 92.821 ;
     RECT  49.032 92.821 49.122 92.975 ;
     RECT  54.144 92.821 56.142 92.975 ;
     RECT  49.935 91.589 50.217 93.055 ;
     RECT  51.66 90.923 52.254 93.055 ;
     RECT  44.535 90.041 44.817 93.091 ;
     RECT  46.188 92.821 46.386 93.209 ;
     RECT  54.144 92.975 54.414 93.209 ;
     RECT  44.535 93.091 45.27 93.211 ;
     RECT  44.316 93.211 45.27 93.251 ;
     RECT  44.46 93.251 45.27 93.281 ;
     RECT  55.188 92.975 56.142 93.451 ;
     RECT  57.024 92.443 57.042 93.451 ;
     RECT  57.888 93.361 57.906 93.479 ;
     RECT  44.46 93.281 45.054 93.515 ;
     RECT  55.188 93.451 57.042 93.559 ;
     RECT  55.188 93.559 57.186 93.587 ;
     RECT  51.588 93.055 52.254 93.595 ;
     RECT  49.896 93.055 50.217 93.631 ;
     RECT  51.192 93.595 52.254 93.631 ;
     RECT  53.28 93.559 53.298 93.631 ;
     RECT  54.144 93.209 54.234 93.631 ;
     RECT  49.896 93.631 52.254 93.749 ;
     RECT  53.28 93.631 54.234 93.749 ;
     RECT  55.296 93.587 57.186 93.749 ;
     RECT  51.66 93.749 52.254 93.757 ;
     RECT  53.28 93.749 54.162 93.757 ;
     RECT  51.66 93.757 54.162 93.785 ;
     RECT  51.66 93.785 53.298 93.821 ;
     RECT  47.376 92.705 47.394 93.991 ;
     RECT  49.896 93.749 50.49 94.019 ;
     RECT  47.376 93.991 48.042 94.099 ;
     RECT  49.104 92.975 49.122 94.099 ;
     RECT  47.376 94.099 49.122 94.261 ;
     RECT  47.304 94.261 49.122 94.289 ;
     RECT  55.335 93.749 56.97 94.289 ;
     RECT  46.368 93.209 46.386 94.603 ;
     RECT  44.46 93.515 44.817 94.795 ;
     RECT  45.864 94.603 46.386 94.829 ;
     RECT  45.864 94.829 46.026 94.901 ;
     RECT  44.46 94.795 45.09 94.981 ;
     RECT  55.335 94.289 56.142 95.071 ;
     RECT  54.144 93.785 54.162 95.131 ;
     RECT  54.9 95.071 56.142 95.131 ;
     RECT  54.144 95.131 56.142 95.171 ;
     RECT  47.304 94.289 48.042 95.639 ;
     RECT  56.952 94.289 56.97 95.719 ;
     RECT  54.144 95.171 54.162 96.061 ;
     RECT  54.9 95.171 56.142 96.061 ;
     RECT  54.144 96.061 56.142 96.287 ;
     RECT  51.66 93.821 52.902 96.295 ;
     RECT  56.952 95.719 57.438 96.331 ;
     RECT  56.484 96.331 57.438 96.449 ;
     RECT  49.935 94.019 50.49 96.565 ;
     RECT  51.408 96.295 52.902 96.565 ;
     RECT  49.104 94.289 49.122 96.601 ;
     RECT  56.808 96.449 57.438 96.629 ;
     RECT  44.46 94.981 45.306 96.715 ;
     RECT  48.888 96.601 49.122 96.719 ;
     RECT  54.144 96.287 55.617 96.719 ;
     RECT  47.304 95.639 47.466 96.763 ;
     RECT  44.46 96.715 45.99 96.791 ;
     RECT  47.304 96.763 47.934 96.8 ;
     RECT  49.935 96.565 52.902 96.811 ;
     RECT  47.304 96.8 47.862 96.827 ;
     RECT  48.888 96.719 48.906 96.827 ;
     RECT  49.935 96.811 53.406 96.827 ;
     RECT  54.144 96.719 54.342 96.827 ;
     RECT  49.935 96.827 50.886 96.863 ;
     RECT  51.66 96.827 53.406 96.863 ;
     RECT  46.764 96.835 46.962 96.871 ;
     RECT  54.144 96.827 54.234 96.871 ;
     RECT  47.844 96.827 47.862 96.989 ;
     RECT  48.708 96.835 48.726 96.989 ;
     RECT  53.568 96.871 54.234 96.989 ;
     RECT  43.02 90.275 43.038 97.259 ;
     RECT  44.46 96.791 45.306 97.259 ;
     RECT  56.808 96.629 57.258 97.259 ;
     RECT  41.58 97.375 41.598 97.517 ;
     RECT  46.152 96.871 46.962 97.517 ;
     RECT  51.66 96.863 52.794 97.517 ;
     RECT  53.568 96.989 54.198 97.517 ;
     RECT  44.46 97.259 44.874 97.529 ;
     RECT  49.935 96.863 50.31 97.529 ;
     RECT  51.66 97.517 52.254 97.529 ;
     RECT  53.568 97.517 53.586 97.529 ;
     RECT  56.808 97.259 56.826 97.529 ;
     RECT  46.152 97.517 46.782 97.645 ;
     RECT  53.424 97.645 53.442 97.709 ;
     RECT  56.664 97.645 56.682 97.709 ;
     RECT  1.335 1.333 1.617 98.027 ;
     RECT  6.735 1.333 7.017 98.027 ;
     RECT  12.135 1.333 12.417 98.027 ;
     RECT  17.535 1.333 17.817 98.027 ;
     RECT  22.935 1.333 23.217 98.027 ;
     RECT  28.335 1.333 28.617 98.027 ;
     RECT  33.735 1.333 34.017 98.027 ;
     RECT  39.135 52.043 39.417 98.027 ;
     RECT  49.935 97.529 50.217 98.027 ;
     RECT  55.335 96.719 55.617 98.027 ;
     RECT  60.735 1.333 61.017 98.027 ;
     RECT  66.135 1.333 66.417 98.027 ;
     RECT  71.535 1.333 71.817 98.027 ;
     RECT  76.935 1.333 77.217 98.027 ;
     RECT  82.335 1.333 82.617 98.027 ;
     RECT  87.735 1.333 88.017 98.027 ;
     RECT  93.135 1.333 93.417 98.027 ;
     RECT  98.535 59.933 98.817 98.027 ;
     RECT  51.66 97.529 52.11 98.045 ;
     RECT  44.535 97.529 44.874 98.189 ;
     RECT  1.335 98.027 1.425 98.297 ;
     RECT  6.735 98.027 6.825 98.297 ;
     RECT  12.135 98.027 12.225 98.297 ;
     RECT  17.535 98.027 17.625 98.297 ;
     RECT  22.935 98.027 23.025 98.297 ;
     RECT  28.335 98.027 28.425 98.297 ;
     RECT  33.735 98.027 33.825 98.297 ;
     RECT  39.135 98.027 39.225 98.297 ;
     RECT  44.535 98.189 44.625 98.297 ;
     RECT  49.935 98.027 50.094 98.297 ;
     RECT  55.335 98.027 55.425 98.297 ;
     RECT  60.735 98.027 60.825 98.297 ;
     RECT  66.135 98.027 66.225 98.297 ;
     RECT  71.535 98.027 71.625 98.297 ;
     RECT  76.935 98.027 77.025 98.297 ;
     RECT  82.335 98.027 82.425 98.297 ;
     RECT  87.735 98.027 87.825 98.297 ;
     RECT  93.135 98.027 93.225 98.297 ;
     RECT  98.535 98.027 98.625 98.297 ;
     RECT  50.076 98.297 50.094 98.429 ;
     RECT  46.044 97.645 46.782 98.669 ;
     RECT  51.66 98.045 51.678 98.669 ;
     RECT  58.716 97.375 58.734 98.669 ;
     RECT  46.764 98.669 46.782 99.245 ;
    LAYER M4 ;
     RECT  0.06 46.464 0.131 46.488 ;
     RECT  0.06 52.032 0.137 54.072 ;
     RECT  0.06 56.16 0.137 56.184 ;
     RECT  0.06 58.56 0.137 58.584 ;
     RECT  0.06 49.536 1.328 49.56 ;
     RECT  0.137 52.032 1.328 53.112 ;
     RECT  1.328 1.068 1.432 98.292 ;
     RECT  1.432 1.338 1.624 98.022 ;
     RECT  1.624 49.536 6.728 49.56 ;
     RECT  6.728 1.068 6.832 98.292 ;
     RECT  6.832 1.338 7.024 98.022 ;
     RECT  7.024 49.536 12.128 49.56 ;
     RECT  12.128 1.068 12.232 98.292 ;
     RECT  12.232 1.338 12.424 98.022 ;
     RECT  12.424 49.536 17.528 49.56 ;
     RECT  17.528 1.068 17.632 98.292 ;
     RECT  17.632 1.338 17.824 98.022 ;
     RECT  17.824 49.536 22.928 49.56 ;
     RECT  22.928 1.068 23.032 98.292 ;
     RECT  23.032 1.338 23.224 98.022 ;
     RECT  23.224 49.536 28.328 49.56 ;
     RECT  28.328 1.068 28.432 98.292 ;
     RECT  28.432 1.338 28.624 98.022 ;
     RECT  28.624 49.536 33.728 49.56 ;
     RECT  33.728 1.068 33.832 98.292 ;
     RECT  33.832 1.338 34.024 98.022 ;
     RECT  34.024 49.536 39.128 49.56 ;
     RECT  39.128 1.068 39.232 98.292 ;
     RECT  39.232 1.338 39.424 98.022 ;
     RECT  39.424 49.536 40.061 49.56 ;
     RECT  40.981 45.216 41.068 45.24 ;
     RECT  41.497 51.648 41.603 51.672 ;
     RECT  41.365 97.488 41.609 97.512 ;
     RECT  41.317 44.976 41.933 45 ;
     RECT  41.605 49.344 42.179 49.368 ;
     RECT  41.893 81.168 42.179 81.192 ;
     RECT  41.677 84 42.179 84.024 ;
     RECT  42.469 40.896 42.755 40.92 ;
     RECT  42.865 89.952 43.331 89.976 ;
     RECT  43.333 81.216 43.475 81.24 ;
     RECT  44.125 0.096 44.405 0.12 ;
     RECT  44.225 1.152 44.405 1.176 ;
     RECT  44.405 0.096 44.528 1.176 ;
     RECT  43.837 36.384 44.528 36.408 ;
     RECT  44.012 42 44.528 42.024 ;
     RECT  43.868 49.2 44.528 49.224 ;
     RECT  43.724 51.648 44.528 51.672 ;
     RECT  43.621 84.048 44.528 84.072 ;
     RECT  44.3 93.216 44.528 93.24 ;
     RECT  44.528 0.096 44.632 98.292 ;
     RECT  44.632 1.338 44.824 98.184 ;
     RECT  44.824 98.16 44.885 98.184 ;
     RECT  44.632 0.096 44.963 0.12 ;
     RECT  44.824 37.056 44.963 37.08 ;
     RECT  44.824 39.168 45.001 39.192 ;
     RECT  44.824 86.544 45.539 86.568 ;
     RECT  44.824 44.16 45.58 44.184 ;
     RECT  44.824 94.8 45.587 94.824 ;
     RECT  44.824 81.216 45.724 81.24 ;
     RECT  44.824 83.376 45.779 83.4 ;
     RECT  44.824 40.416 45.82 40.44 ;
     RECT  45.877 96.72 46.019 96.744 ;
     RECT  46.033 98.64 46.211 98.664 ;
     RECT  46.309 90 46.397 90.024 ;
     RECT  46.405 92.64 46.492 92.664 ;
     RECT  46.46 37.872 46.547 37.896 ;
     RECT  45.953 0.096 46.595 0.12 ;
     RECT  46.604 0.528 46.691 0.552 ;
     RECT  46.741 99.216 46.828 99.24 ;
     RECT  46.892 97.488 46.979 97.512 ;
     RECT  46.681 34.368 47.149 34.392 ;
     RECT  47.257 84.288 47.317 84.312 ;
     RECT  47.317 84.192 47.341 84.312 ;
     RECT  47.317 51.648 47.549 51.672 ;
     RECT  47.468 41.856 47.555 41.88 ;
     RECT  47.341 84.192 47.621 84.216 ;
     RECT  47.149 34.272 47.689 34.392 ;
     RECT  47.761 51.072 47.891 51.096 ;
     RECT  47.861 96.768 47.945 96.792 ;
     RECT  47.869 94.128 47.953 94.152 ;
     RECT  47.689 34.272 48.085 34.872 ;
     RECT  48.044 37.056 48.131 37.08 ;
     RECT  48.085 34.272 48.169 35.352 ;
     RECT  48.169 34.272 48.275 34.824 ;
     RECT  48.437 40.416 48.521 40.44 ;
     RECT  48.373 27.936 48.557 27.96 ;
     RECT  48.653 0.096 48.737 0.12 ;
     RECT  48.517 34.176 49.805 34.2 ;
     RECT  49.909 0.096 49.928 0.12 ;
     RECT  49.805 33.6 49.928 34.2 ;
     RECT  49.621 68.352 49.928 68.376 ;
     RECT  48.985 90.864 49.928 90.888 ;
     RECT  49.928 0.096 50.005 98.292 ;
     RECT  50.005 0.096 50.032 98.424 ;
     RECT  50.032 1.338 50.105 98.424 ;
     RECT  50.105 1.338 50.224 98.022 ;
     RECT  50.224 33.504 50.339 34.44 ;
     RECT  50.224 96.816 50.339 96.84 ;
     RECT  50.224 93.648 50.401 93.672 ;
     RECT  50.224 84.864 50.465 85.128 ;
     RECT  50.224 47.328 50.573 47.352 ;
     RECT  50.224 41.136 50.723 41.16 ;
     RECT  50.465 85.104 50.723 85.128 ;
     RECT  50.224 37.392 51.059 37.416 ;
     RECT  50.339 33.552 51.148 34.44 ;
     RECT  50.224 50.688 51.149 50.712 ;
     RECT  50.032 0.096 51.337 0.12 ;
     RECT  51.533 34.608 51.617 34.872 ;
     RECT  51.617 34.608 51.625 34.632 ;
     RECT  51.649 98.64 51.971 98.664 ;
     RECT  51.98 84.912 52.067 84.936 ;
     RECT  51.877 90.912 52.163 90.936 ;
     RECT  52.081 98.016 52.259 98.04 ;
     RECT  51.148 33.552 52.307 33.576 ;
     RECT  52.364 36.384 52.451 36.408 ;
     RECT  52.453 42.768 52.553 42.792 ;
     RECT  52.453 31.296 52.661 31.32 ;
     RECT  52.693 93.792 52.78 93.816 ;
     RECT  52.657 50.688 53.027 50.712 ;
     RECT  52.748 97.488 53.365 97.512 ;
     RECT  53.365 96.816 53.413 97.512 ;
     RECT  53.413 96.816 53.452 97.704 ;
     RECT  53.452 97.488 53.507 97.704 ;
     RECT  53.804 90.336 53.891 90.36 ;
     RECT  53.948 87.552 54.035 87.576 ;
     RECT  53.629 38.736 54.131 38.76 ;
     RECT  54.229 44.592 54.316 44.616 ;
     RECT  54.229 92.688 54.316 92.712 ;
     RECT  55.061 0.096 55.145 0.12 ;
     RECT  55.189 36.336 55.328 36.36 ;
     RECT  54.133 41.136 55.328 41.16 ;
     RECT  54.629 48.624 55.328 48.648 ;
     RECT  55.189 51.984 55.328 52.008 ;
     RECT  54.709 95.136 55.328 95.16 ;
     RECT  53.507 97.488 55.328 97.512 ;
     RECT  55.328 1.068 55.432 98.292 ;
     RECT  55.432 1.338 55.624 98.022 ;
     RECT  55.624 41.76 56.009 41.784 ;
     RECT  55.624 38.688 56.045 38.712 ;
     RECT  55.624 45.264 56.045 45.288 ;
     RECT  55.624 96.336 56.513 96.36 ;
     RECT  55.624 93.984 56.657 94.008 ;
     RECT  56.653 97.68 56.963 97.704 ;
     RECT  55.624 48.384 56.965 48.408 ;
     RECT  56.965 48.384 56.977 48.696 ;
     RECT  56.897 0.096 56.981 0.12 ;
     RECT  56.977 47.856 57.052 48.696 ;
     RECT  57.052 47.856 57.953 47.88 ;
     RECT  58.261 99.168 58.403 99.192 ;
     RECT  58.705 98.64 59.171 98.664 ;
     RECT  60.728 1.068 60.832 98.292 ;
     RECT  60.832 1.338 61.024 98.022 ;
     RECT  66.128 1.068 66.232 98.292 ;
     RECT  66.232 1.338 66.424 98.022 ;
     RECT  71.528 1.068 71.632 98.292 ;
     RECT  71.632 1.338 71.824 98.022 ;
     RECT  76.928 1.068 77.032 98.292 ;
     RECT  77.032 1.338 77.224 98.022 ;
     RECT  82.328 1.068 82.432 98.292 ;
     RECT  82.432 1.338 82.624 98.022 ;
     RECT  87.728 1.068 87.832 98.292 ;
     RECT  87.832 1.338 88.024 98.022 ;
     RECT  93.128 1.068 93.232 98.292 ;
     RECT  93.232 1.338 93.424 98.022 ;
     RECT  98.528 1.068 98.632 98.292 ;
     RECT  98.632 1.338 98.824 98.022 ;
     RECT  98.824 46.56 100.069 47.352 ;
     RECT  100.069 46.56 100.188 48.312 ;
     RECT  98.824 59.904 100.188 59.928 ;
    LAYER M5 ;
     RECT  43.872 0.016 44.664 0.085 ;
     RECT  45.984 0.016 46.68 0.131 ;
     RECT  48.384 0.016 48.696 0.131 ;
     RECT  51.264 0.016 51.288 0.131 ;
     RECT  55.104 0.016 55.128 0.131 ;
     RECT  56.928 0.016 56.952 0.131 ;
     RECT  46.464 0.131 46.68 0.141 ;
     RECT  43.872 0.085 44.952 0.171 ;
     RECT  46.656 0.141 46.68 0.563 ;
     RECT  49.92 0.016 49.944 1.057 ;
     RECT  44.256 0.171 44.952 1.187 ;
     RECT  1.32 1.057 1.44 1.327 ;
     RECT  6.72 1.057 6.84 1.327 ;
     RECT  12.12 1.057 12.24 1.327 ;
     RECT  17.52 1.057 17.64 1.327 ;
     RECT  22.92 1.057 23.04 1.327 ;
     RECT  28.32 1.057 28.44 1.327 ;
     RECT  33.72 1.057 33.84 1.327 ;
     RECT  39.12 1.057 39.24 1.327 ;
     RECT  49.92 1.057 50.04 1.327 ;
     RECT  55.32 1.057 55.44 1.327 ;
     RECT  60.72 1.057 60.84 1.327 ;
     RECT  66.12 1.057 66.24 1.327 ;
     RECT  71.52 1.057 71.64 1.327 ;
     RECT  76.92 1.057 77.04 1.327 ;
     RECT  82.32 1.057 82.44 1.327 ;
     RECT  87.72 1.057 87.84 1.327 ;
     RECT  93.12 1.057 93.24 1.327 ;
     RECT  98.52 1.057 98.64 1.327 ;
     RECT  48.384 0.131 48.408 27.971 ;
     RECT  52.464 31.285 52.488 31.369 ;
     RECT  49.92 1.327 50.232 33.461 ;
     RECT  49.92 33.461 50.328 33.589 ;
     RECT  52.272 33.525 52.296 33.613 ;
     RECT  49.824 33.589 50.328 33.673 ;
     RECT  48.24 33.461 48.264 34.165 ;
     RECT  48.24 34.165 48.552 34.405 ;
     RECT  49.92 33.673 50.328 34.405 ;
     RECT  49.92 34.405 51.096 34.597 ;
     RECT  49.92 34.597 51.576 34.667 ;
     RECT  48 34.405 48.552 34.799 ;
     RECT  47.856 34.799 48.552 34.859 ;
     RECT  47.856 34.859 48.12 34.883 ;
     RECT  51.552 34.667 51.576 34.883 ;
     RECT  55.32 1.327 55.632 36.325 ;
     RECT  44.52 1.187 44.952 36.373 ;
     RECT  55.2 36.325 55.632 36.409 ;
     RECT  52.416 36.341 52.44 36.429 ;
     RECT  43.872 36.373 44.952 36.459 ;
     RECT  44.52 36.459 44.952 37.091 ;
     RECT  48.096 34.883 48.12 37.091 ;
     RECT  49.92 34.667 50.232 37.365 ;
     RECT  49.92 37.365 51.048 37.453 ;
     RECT  46.512 37.813 46.536 37.907 ;
     RECT  55.32 36.409 55.632 38.639 ;
     RECT  54 38.645 54.024 38.687 ;
     RECT  55.32 38.639 55.896 38.723 ;
     RECT  54 38.687 54.12 38.771 ;
     RECT  44.52 37.091 44.832 39.093 ;
     RECT  44.52 39.093 44.952 39.203 ;
     RECT  44.52 39.203 44.832 40.405 ;
     RECT  44.52 40.405 45.768 40.491 ;
     RECT  48.48 40.405 48.504 40.491 ;
     RECT  42.72 40.885 42.744 40.969 ;
     RECT  55.32 38.723 55.632 41.077 ;
     RECT  49.92 37.453 50.232 41.125 ;
     RECT  54.384 41.077 55.632 41.125 ;
     RECT  54.144 41.125 55.632 41.171 ;
     RECT  49.92 41.125 50.712 41.209 ;
     RECT  54.144 41.171 54.168 41.209 ;
     RECT  55.32 41.171 55.632 41.749 ;
     RECT  55.32 41.749 55.896 41.835 ;
     RECT  47.52 41.781 47.544 41.891 ;
     RECT  44.52 40.491 44.832 41.989 ;
     RECT  44.064 41.989 44.832 42.091 ;
     RECT  52.464 42.677 52.488 42.803 ;
     RECT  44.52 42.091 44.832 44.149 ;
     RECT  44.52 44.149 45.528 44.459 ;
     RECT  54.24 44.533 54.264 44.627 ;
     RECT  55.32 41.835 55.632 45.253 ;
     RECT  55.32 45.253 55.992 45.483 ;
     RECT  40.992 45.205 41.016 45.547 ;
     RECT  0.096 46.419 0.12 46.507 ;
     RECT  55.32 45.483 55.632 48.373 ;
     RECT  100.08 48.277 100.104 48.427 ;
     RECT  55.32 48.373 56.424 48.457 ;
     RECT  55.32 48.457 55.632 48.613 ;
     RECT  54.672 48.613 55.632 48.697 ;
     RECT  56.976 48.629 57 48.717 ;
     RECT  44.52 44.459 44.832 49.141 ;
     RECT  43.92 49.141 44.832 49.387 ;
     RECT  42.144 49.333 42.168 49.417 ;
     RECT  49.92 41.209 50.232 50.677 ;
     RECT  52.992 50.677 53.016 50.859 ;
     RECT  49.92 50.677 50.76 51.115 ;
     RECT  47.856 51.061 47.88 51.145 ;
     RECT  44.52 49.387 44.832 51.603 ;
     RECT  43.776 51.603 44.832 51.691 ;
     RECT  41.568 51.637 41.592 51.721 ;
     RECT  47.328 51.637 47.352 51.721 ;
     RECT  55.32 48.697 55.632 51.935 ;
     RECT  55.2 51.935 55.632 52.019 ;
     RECT  49.92 51.115 50.232 68.307 ;
     RECT  49.632 68.307 50.232 68.395 ;
     RECT  43.344 81.141 43.368 81.171 ;
     RECT  44.52 51.691 44.832 81.171 ;
     RECT  42.144 81.119 42.168 81.203 ;
     RECT  43.344 81.171 43.464 81.251 ;
     RECT  43.44 81.251 43.464 81.259 ;
     RECT  44.52 81.171 45.672 81.259 ;
     RECT  44.52 81.259 44.832 83.347 ;
     RECT  44.52 83.347 45.768 83.435 ;
     RECT  44.52 83.435 44.832 84.021 ;
     RECT  42.144 83.989 42.168 84.075 ;
     RECT  43.632 84.021 44.832 84.109 ;
     RECT  43.872 84.109 44.832 84.139 ;
     RECT  47.424 84.085 47.448 84.143 ;
     RECT  47.328 84.143 47.448 84.227 ;
     RECT  49.92 68.395 50.232 84.277 ;
     RECT  47.28 84.277 47.304 84.361 ;
     RECT  49.92 84.277 50.328 85.093 ;
     RECT  52.032 84.883 52.056 85.163 ;
     RECT  49.92 85.093 50.712 85.177 ;
     RECT  44.52 84.139 44.832 86.517 ;
     RECT  44.52 86.517 45.528 86.605 ;
     RECT  54 87.477 54.024 87.587 ;
     RECT  43.296 89.941 43.32 90.027 ;
     RECT  46.32 89.973 46.344 90.061 ;
     RECT  53.856 90.293 53.88 90.381 ;
     RECT  49.92 85.177 50.232 90.853 ;
     RECT  51.888 90.863 51.912 90.901 ;
     RECT  49.008 90.853 50.232 90.937 ;
     RECT  51.888 90.901 52.152 90.947 ;
     RECT  52.128 90.947 52.152 90.987 ;
     RECT  46.416 92.597 46.44 92.685 ;
     RECT  54.24 92.677 54.264 92.779 ;
     RECT  44.52 86.605 44.832 93.109 ;
     RECT  44.352 93.109 44.832 93.251 ;
     RECT  49.92 90.937 50.232 93.637 ;
     RECT  55.32 52.019 55.632 93.973 ;
     RECT  49.92 93.637 50.376 94.059 ;
     RECT  52.704 93.781 52.728 94.059 ;
     RECT  55.32 93.973 56.472 94.059 ;
     RECT  47.904 94.117 47.928 94.201 ;
     RECT  44.52 93.251 44.832 94.751 ;
     RECT  44.52 94.751 45.576 94.835 ;
     RECT  55.32 94.059 55.632 95.125 ;
     RECT  54.72 95.125 55.632 95.211 ;
     RECT  55.32 95.211 55.632 96.287 ;
     RECT  55.32 96.287 56.472 96.371 ;
     RECT  45.984 96.693 46.008 96.709 ;
     RECT  45.888 96.709 46.008 96.781 ;
     RECT  49.92 94.059 50.232 96.805 ;
     RECT  45.888 96.781 45.912 96.811 ;
     RECT  47.904 96.757 47.928 96.841 ;
     RECT  49.92 96.805 50.328 96.889 ;
     RECT  53.376 96.787 53.4 97.477 ;
     RECT  55.32 96.371 55.632 97.477 ;
     RECT  52.8 97.477 55.632 98.005 ;
     RECT  1.32 1.327 1.632 98.033 ;
     RECT  6.72 1.327 7.032 98.033 ;
     RECT  12.12 1.327 12.432 98.033 ;
     RECT  17.52 1.327 17.832 98.033 ;
     RECT  22.92 1.327 23.232 98.033 ;
     RECT  28.32 1.327 28.632 98.033 ;
     RECT  33.72 1.327 34.032 98.033 ;
     RECT  39.12 1.327 39.432 98.033 ;
     RECT  49.92 96.889 50.232 98.033 ;
     RECT  52.224 98.005 55.632 98.033 ;
     RECT  60.72 1.327 61.032 98.033 ;
     RECT  66.12 1.327 66.432 98.033 ;
     RECT  71.52 1.327 71.832 98.033 ;
     RECT  76.92 1.327 77.232 98.033 ;
     RECT  82.32 1.327 82.632 98.033 ;
     RECT  87.72 1.327 88.032 98.033 ;
     RECT  93.12 1.327 93.432 98.033 ;
     RECT  98.52 1.327 98.832 98.033 ;
     RECT  44.52 94.835 44.832 98.149 ;
     RECT  1.32 98.033 1.44 98.303 ;
     RECT  6.72 98.033 6.84 98.303 ;
     RECT  12.12 98.033 12.24 98.303 ;
     RECT  17.52 98.033 17.64 98.303 ;
     RECT  22.92 98.033 23.04 98.303 ;
     RECT  28.32 98.033 28.44 98.303 ;
     RECT  33.72 98.033 33.84 98.303 ;
     RECT  39.12 98.033 39.24 98.303 ;
     RECT  44.52 98.149 44.856 98.303 ;
     RECT  49.92 98.033 50.04 98.303 ;
     RECT  52.224 98.033 55.44 98.303 ;
     RECT  60.72 98.033 60.84 98.303 ;
     RECT  66.12 98.033 66.24 98.303 ;
     RECT  71.52 98.033 71.64 98.303 ;
     RECT  76.92 98.033 77.04 98.303 ;
     RECT  82.32 98.033 82.44 98.303 ;
     RECT  87.72 98.033 87.84 98.303 ;
     RECT  93.12 98.033 93.24 98.303 ;
     RECT  98.52 98.033 98.64 98.303 ;
     RECT  46.944 97.477 46.968 98.629 ;
     RECT  52.224 98.303 54.36 98.629 ;
     RECT  59.136 98.629 59.16 99.157 ;
     RECT  58.272 99.157 59.16 99.307 ;
     RECT  41.376 97.477 41.4 99.344 ;
     RECT  44.832 98.303 44.856 99.344 ;
     RECT  46.176 98.629 46.968 99.344 ;
     RECT  50.016 98.303 50.04 99.344 ;
     RECT  51.936 98.629 54.36 99.344 ;
     RECT  56.928 97.669 56.952 99.344 ;
     RECT  58.368 99.307 59.16 99.344 ;
    LAYER M6 ;
     RECT  0.085 46.464 0.117 46.496 ;
     RECT  0.117 45.504 0.171 46.496 ;
     RECT  0.171 45.504 1.08 45.536 ;
     RECT  1.08 44.649 41.027 45.536 ;
     RECT  1.08 50.049 41.557 50.721 ;
     RECT  41.557 50.049 42.133 51.68 ;
     RECT  1.08 82.449 42.133 83.121 ;
     RECT  1.08 39.249 42.709 39.921 ;
     RECT  42.133 81.152 43.379 84.064 ;
     RECT  1.08 33.849 43.829 34.521 ;
     RECT  43.379 81.216 43.861 84.064 ;
     RECT  43.829 0.128 43.907 0.16 ;
     RECT  42.133 49.344 43.909 51.68 ;
     RECT  41.027 44.649 43.957 45.321 ;
     RECT  43.909 49.152 44.011 51.68 ;
     RECT  42.709 39.249 44.053 40.928 ;
     RECT  44.053 39.249 44.139 42.08 ;
     RECT  1.08 93.249 44.341 93.921 ;
     RECT  44.139 39.249 44.898 40.48 ;
     RECT  44.898 39.104 44.971 40.48 ;
     RECT  43.957 44.416 45.539 45.321 ;
     RECT  44.341 93.12 45.541 93.921 ;
     RECT  45.474 86.528 45.547 86.56 ;
     RECT  43.861 81.216 45.694 84.128 ;
     RECT  45.694 82.449 45.749 84.128 ;
     RECT  45.877 96.768 45.973 96.8 ;
     RECT  45.541 93.12 46.389 94.816 ;
     RECT  43.285 89.984 46.443 90.016 ;
     RECT  46.389 92.608 46.443 94.816 ;
     RECT  45.973 96.704 46.443 96.8 ;
     RECT  46.443 92.608 46.462 94.176 ;
     RECT  46.501 37.824 46.571 37.856 ;
     RECT  45.749 82.449 47.269 84.192 ;
     RECT  44.011 50.049 47.363 51.68 ;
     RECT  47.509 41.792 47.595 41.824 ;
     RECT  43.829 33.849 47.845 34.72 ;
     RECT  46.462 93.249 47.939 94.176 ;
     RECT  46.443 96.768 47.939 96.8 ;
     RECT  43.861 36.416 48.131 36.448 ;
     RECT  46.453 0.064 48.171 0.096 ;
     RECT  47.845 33.849 48.229 34.848 ;
     RECT  44.971 39.249 48.515 40.48 ;
     RECT  48.229 33.472 48.563 34.848 ;
     RECT  49.621 68.352 50.027 68.384 ;
     RECT  48.563 33.472 50.339 34.656 ;
     RECT  47.269 82.449 50.339 84.32 ;
     RECT  47.939 93.249 50.341 93.921 ;
     RECT  48.515 39.249 50.677 39.921 ;
     RECT  47.363 50.049 50.771 51.104 ;
     RECT  50.339 33.6 51.509 34.656 ;
     RECT  51.509 33.6 51.587 34.848 ;
     RECT  51.013 37.376 51.893 37.408 ;
     RECT  48.997 90.88 51.923 90.912 ;
     RECT  51.893 36.352 51.947 37.408 ;
     RECT  50.677 85.12 52.021 85.152 ;
     RECT  52.021 84.928 52.067 85.152 ;
     RECT  51.587 33.6 52.261 34.521 ;
     RECT  52.261 33.536 52.331 34.521 ;
     RECT  52.277 31.296 52.499 31.328 ;
     RECT  50.771 50.049 52.981 50.721 ;
     RECT  52.117 90.944 53.799 90.976 ;
     RECT  50.677 39.249 53.989 41.184 ;
     RECT  1.08 87.849 53.989 88.521 ;
     RECT  52.067 84.928 54.059 84.96 ;
     RECT  53.989 87.488 54.059 88.521 ;
     RECT  53.799 90.304 54.059 90.976 ;
     RECT  50.341 93.249 54.069 94.048 ;
     RECT  54.059 90.944 54.123 90.976 ;
     RECT  45.539 44.649 54.229 45.321 ;
     RECT  53.989 38.656 54.261 41.184 ;
     RECT  52.453 42.688 54.261 42.72 ;
     RECT  54.229 44.544 54.261 45.321 ;
     RECT  54.069 92.736 54.275 94.048 ;
     RECT  54.261 38.656 54.315 42.72 ;
     RECT  54.261 44.544 54.315 45.472 ;
     RECT  52.981 50.049 54.389 50.848 ;
     RECT  54.315 38.656 54.443 41.824 ;
     RECT  54.275 93.249 54.709 94.048 ;
     RECT  50.293 96.832 54.709 96.864 ;
     RECT  54.709 93.249 54.763 96.864 ;
     RECT  54.763 93.249 54.778 96.352 ;
     RECT  51.947 36.352 55.235 36.384 ;
     RECT  54.389 50.049 55.235 52 ;
     RECT  54.443 38.656 55.907 39.921 ;
     RECT  54.443 41.792 55.907 41.824 ;
     RECT  54.315 44.649 56.003 45.472 ;
     RECT  54.661 48.64 56.389 48.672 ;
     RECT  54.778 93.249 56.483 94.048 ;
     RECT  54.778 96.32 56.483 96.352 ;
     RECT  56.389 48.384 57.011 48.672 ;
     RECT  49.653 99.264 58.307 99.296 ;
     RECT  1.08 1.449 99.144 2.121 ;
     RECT  1.08 6.849 99.144 7.521 ;
     RECT  1.08 12.249 99.144 12.921 ;
     RECT  1.08 17.649 99.144 18.321 ;
     RECT  1.08 23.049 99.144 23.721 ;
     RECT  1.08 28.449 99.144 29.121 ;
     RECT  52.331 33.849 99.144 34.521 ;
     RECT  55.907 39.249 99.144 39.921 ;
     RECT  56.003 44.649 99.144 45.321 ;
     RECT  55.235 50.049 99.144 50.721 ;
     RECT  1.08 55.449 99.144 56.121 ;
     RECT  1.08 60.849 99.144 61.521 ;
     RECT  1.08 66.249 99.144 66.921 ;
     RECT  1.08 71.649 99.144 72.321 ;
     RECT  1.08 77.049 99.144 77.721 ;
     RECT  50.339 82.449 99.144 83.121 ;
     RECT  54.059 87.849 99.144 88.521 ;
     RECT  56.483 93.249 99.144 93.921 ;
     RECT  57.011 48.384 100.115 48.416 ;
    LAYER M7 ;
     RECT  52.288 31.285 52.32 33.579 ;
     RECT  48.128 0.053 48.16 34.667 ;
     RECT  43.84 0.117 43.872 34.731 ;
     RECT  51.52 33.589 51.552 34.859 ;
     RECT  51.904 36.341 51.936 37.419 ;
     RECT  46.528 36.405 46.56 37.867 ;
     RECT  44.928 39.093 44.96 40.437 ;
     RECT  44.096 40.437 44.96 40.491 ;
     RECT  54.4 38.709 54.432 41.781 ;
     RECT  47.552 40.437 47.584 41.835 ;
     RECT  54.272 41.781 54.432 41.835 ;
     RECT  44.096 40.491 44.128 44.405 ;
     RECT  43.968 44.405 44.128 44.459 ;
     RECT  54.272 41.835 54.304 45.429 ;
     RECT  54.272 45.429 54.432 45.483 ;
     RECT  0.128 45.493 0.16 46.507 ;
     RECT  43.968 44.459 44 51.691 ;
     RECT  54.4 45.483 54.432 52.011 ;
     RECT  49.984 51.061 50.016 68.341 ;
     RECT  45.632 81.205 45.664 83.381 ;
     RECT  45.632 83.381 45.792 84.085 ;
     RECT  45.504 84.085 45.792 84.203 ;
     RECT  49.664 68.341 50.016 84.331 ;
     RECT  45.504 84.203 45.536 89.973 ;
     RECT  45.504 89.973 46.432 90.027 ;
     RECT  54.016 84.917 54.048 90.293 ;
     RECT  53.824 90.293 54.048 90.933 ;
     RECT  53.824 90.933 54.112 90.987 ;
     RECT  54.08 90.987 54.112 94.005 ;
     RECT  54.08 94.005 54.752 94.059 ;
     RECT  46.4 90.027 46.432 96.747 ;
     RECT  54.72 94.059 54.752 96.875 ;
     RECT  49.664 84.331 49.696 99.307 ;
  END
END ot_hbm_production_clock_digital_body
END LIBRARY
